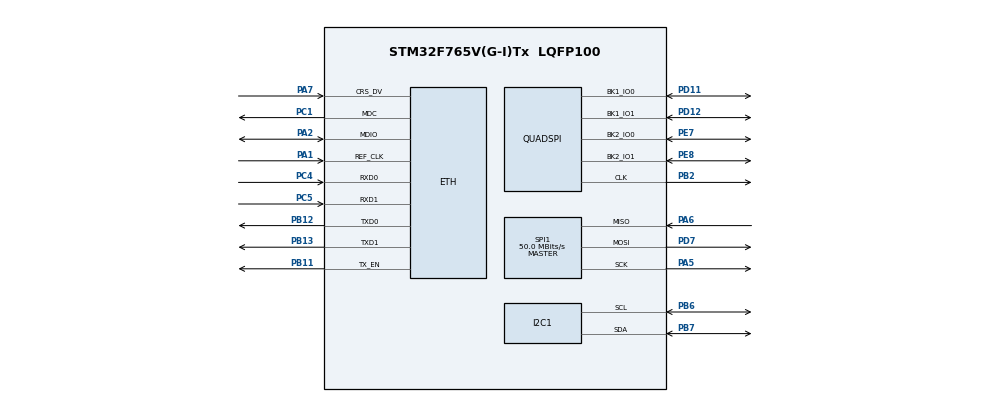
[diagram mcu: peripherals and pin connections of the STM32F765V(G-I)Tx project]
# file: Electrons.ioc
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CORTEX_M7.ART_ACCELERATOR_ENABLE=1
CORTEX_M7.CPU_DCache=Enabled
CORTEX_M7.CPU_ICache=Enabled
CORTEX_M7.PREFETCH_ENABLE=1
ETH.MediaInterface=HAL_ETH_RMII_MODE
I2C1.Timing=0x00C0EAFF
Mcu.Family=STM32F7
Mcu.Name=STM32F765V(G-I)Tx
Mcu.Package=LQFP100
NVIC.PriorityGroup=NVIC_PRIORITYGROUP_4
PA1.Mode=RMII
PA1.Signal=ETH_REF_CLK
PA2.Mode=RMII
PA2.Signal=ETH_MDIO
PA5.Mode=Full_Duplex_Master
PA5.Signal=SPI1_SCK
PA6.Mode=Full_Duplex_Master
PA6.Signal=SPI1_MISO
PA7.Mode=RMII
PA7.Signal=ETH_CRS_DV
PB11.Mode=RMII
PB11.Signal=ETH_TX_EN
PB12.Mode=RMII
PB12.Signal=ETH_TXD0
PB13.Mode=RMII
PB13.Signal=ETH_TXD1
PB2.Mode=Dual_Bank_2IOs
PB2.Signal=QUADSPI_CLK
PB6.Mode=I2C
PB6.Signal=I2C1_SCL
PB7.Mode=I2C
PB7.Signal=I2C1_SDA
PC1.Mode=RMII
PC1.Signal=ETH_MDC
PC4.Mode=RMII
PC4.Signal=ETH_RXD0
PC5.Mode=RMII
PC5.Signal=ETH_RXD1
PD11.Mode=Dual_Bank_2IOs
PD11.Signal=QUADSPI_BK1_IO0
PD12.Mode=Dual_Bank_2IOs
PD12.Signal=QUADSPI_BK1_IO1
PD7.Mode=Full_Duplex_Master
PD7.Signal=SPI1_MOSI
PE7.Mode=Dual_Bank_2IOs
PE7.Signal=QUADSPI_BK2_IO0
PE8.Mode=Dual_Bank_2IOs
PE8.Signal=QUADSPI_BK2_IO1
ProjectManager.HeapSize=0x200
ProjectManager.StackSize=0x400
ProjectManager.TargetToolchain=EWARM V8.50
RCC.AHBFreq_Value=100000000
RCC.APB1CLKDivider=RCC_HCLK_DIV2
RCC.APB1Freq_Value=50000000
RCC.APB1TimFreq_Value=100000000
RCC.APB2Freq_Value=100000000
RCC.APB2TimFreq_Value=100000000
RCC.CortexFreq_Value=100000000
RCC.HCLKFreq_Value=100000000
RCC.HSE_VALUE=25000000
RCC.HSI_VALUE=16000000
RCC.LSE_VALUE=32768
RCC.PLLM=8
RCC.PLLN=100
RCC.SYSCLKFreq_VALUE=100000000
RCC.SYSCLKSource=RCC_SYSCLKSOURCE_PLLCLK
RCC.USBFreq_Value=100000000
RCC.VCOOutputFreq_Value=200000000
SPI1.CalculateBaudRate=50.0 MBits/s
SPI1.Direction=SPI_DIRECTION_2LINES
SPI1.Mode=SPI_MODE_MASTER
SPI1.VirtualType=VM_MASTER
board=custom

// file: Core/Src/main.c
/* USER CODE BEGIN Header */
/**
  ******************************************************************************
  * @file           : main.c
  * @brief          : Main program body
  ******************************************************************************
  * @attention
  *
  * Copyright (c) 2024 STMicroelectronics.
  * All rights reserved.
  *
  * This software is licensed under terms that can be found in the LICENSE file
  * in the root directory of this software component.
  * If no LICENSE file comes with this software, it is provided AS-IS.
  *
  ******************************************************************************
  */
/* USER CODE END Header */
#include "main.h"
#include "string.h"

#if defined ( __ICCARM__ ) /*!< IAR Compiler */
#pragma location=0x2007c000
ETH_DMADescTypeDef  DMARxDscrTab[ETH_RX_DESC_CNT]; /* Ethernet Rx DMA Descriptors */
#pragma location=0x2007c0a0
ETH_DMADescTypeDef  DMATxDscrTab[ETH_TX_DESC_CNT]; /* Ethernet Tx DMA Descriptors */

#elif defined ( __CC_ARM )  /* MDK ARM Compiler */

__attribute__((at(0x2007c000))) ETH_DMADescTypeDef  DMARxDscrTab[ETH_RX_DESC_CNT]; /* Ethernet Rx DMA Descriptors */
__attribute__((at(0x2007c0a0))) ETH_DMADescTypeDef  DMATxDscrTab[ETH_TX_DESC_CNT]; /* Ethernet Tx DMA Descriptors */

#elif defined ( __GNUC__ ) /* GNU Compiler */
ETH_DMADescTypeDef DMARxDscrTab[ETH_RX_DESC_CNT] __attribute__((section(".RxDecripSection"))); /* Ethernet Rx DMA Descriptors */
ETH_DMADescTypeDef DMATxDscrTab[ETH_TX_DESC_CNT] __attribute__((section(".TxDecripSection")));   /* Ethernet Tx DMA Descriptors */

#endif

ETH_TxPacketConfig TxConfig;

ETH_HandleTypeDef heth;

I2C_HandleTypeDef hi2c1;

QSPI_HandleTypeDef hqspi;

SPI_HandleTypeDef hspi1;

void SystemClock_Config(void);
static void MPU_Config(void);
static void MX_GPIO_Init(void);
static void MX_ETH_Init(void);
static void MX_I2C1_Init(void);
static void MX_QUADSPI_Init(void);
static void MX_SPI1_Init(void);

int main(void)
{

  /* MPU Configuration--------------------------------------------------------*/
  MPU_Config();
/* Enable the CPU Cache */

  /* Enable I-Cache---------------------------------------------------------*/
  SCB_EnableICache();

  /* Enable D-Cache---------------------------------------------------------*/
  SCB_EnableDCache();

  /* MCU Configuration--------------------------------------------------------*/

  /* Reset of all peripherals, Initializes the Flash interface and the Systick. */
  HAL_Init();

  /* Configure the system clock */
  SystemClock_Config();

  /* Initialize all configured peripherals */
  MX_GPIO_Init();
  MX_ETH_Init();
  MX_I2C1_Init();
  MX_QUADSPI_Init();
  MX_SPI1_Init();

  /* Infinite loop */
  while (1)
  {

  }
}

void SystemClock_Config(void)
{
  RCC_OscInitTypeDef RCC_OscInitStruct = {0};
  RCC_ClkInitTypeDef RCC_ClkInitStruct = {0};

  /** Configure the main internal regulator output voltage
  */
  __HAL_RCC_PWR_CLK_ENABLE();
  __HAL_PWR_VOLTAGESCALING_CONFIG(PWR_REGULATOR_VOLTAGE_SCALE1);

  /** Initializes the RCC Oscillators according to the specified parameters
  * in the RCC_OscInitTypeDef structure.
  */
  RCC_OscInitStruct.OscillatorType = RCC_OSCILLATORTYPE_HSI;
  RCC_OscInitStruct.HSIState = RCC_HSI_ON;
  RCC_OscInitStruct.HSICalibrationValue = RCC_HSICALIBRATION_DEFAULT;
  RCC_OscInitStruct.PLL.PLLState = RCC_PLL_ON;
  RCC_OscInitStruct.PLL.PLLSource = RCC_PLLSOURCE_HSI;
  RCC_OscInitStruct.PLL.PLLM = 8;
  RCC_OscInitStruct.PLL.PLLN = 216;
  RCC_OscInitStruct.PLL.PLLP = RCC_PLLP_DIV2;
  RCC_OscInitStruct.PLL.PLLQ = 2;
  RCC_OscInitStruct.PLL.PLLR = 2;
  if (HAL_RCC_OscConfig(&RCC_OscInitStruct) != HAL_OK)
  {
    Error_Handler();
  }

  /** Activate the Over-Drive mode
  */
  if (HAL_PWREx_EnableOverDrive() != HAL_OK)
  {
    Error_Handler();
  }

  /** Initializes the CPU, AHB and APB buses clocks
  */
  RCC_ClkInitStruct.ClockType = RCC_CLOCKTYPE_HCLK|RCC_CLOCKTYPE_SYSCLK
                              |RCC_CLOCKTYPE_PCLK1|RCC_CLOCKTYPE_PCLK2;
  RCC_ClkInitStruct.SYSCLKSource = RCC_SYSCLKSOURCE_PLLCLK;
  RCC_ClkInitStruct.AHBCLKDivider = RCC_SYSCLK_DIV1;
  RCC_ClkInitStruct.APB1CLKDivider = RCC_HCLK_DIV4;
  RCC_ClkInitStruct.APB2CLKDivider = RCC_HCLK_DIV2;

  if (HAL_RCC_ClockConfig(&RCC_ClkInitStruct, FLASH_LATENCY_7) != HAL_OK)
  {
    Error_Handler();
  }
}

static void MX_ETH_Init(void)
{

   static uint8_t MACAddr[6];

  heth.Instance = ETH;
  MACAddr[0] = 0x00;
  MACAddr[1] = 0x80;
  MACAddr[2] = 0xE1;
  MACAddr[3] = 0x00;
  MACAddr[4] = 0x00;
  MACAddr[5] = 0x00;
  heth.Init.MACAddr = &MACAddr[0];
  heth.Init.MediaInterface = HAL_ETH_RMII_MODE;
  heth.Init.TxDesc = DMATxDscrTab;
  heth.Init.RxDesc = DMARxDscrTab;
  heth.Init.RxBuffLen = 1524;

  if (HAL_ETH_Init(&heth) != HAL_OK)
  {
    Error_Handler();
  }

  memset(&TxConfig, 0 , sizeof(ETH_TxPacketConfig));
  TxConfig.Attributes = ETH_TX_PACKETS_FEATURES_CSUM | ETH_TX_PACKETS_FEATURES_CRCPAD;
  TxConfig.ChecksumCtrl = ETH_CHECKSUM_IPHDR_PAYLOAD_INSERT_PHDR_CALC;
  TxConfig.CRCPadCtrl = ETH_CRC_PAD_INSERT;

}

static void MX_I2C1_Init(void)
{

  hi2c1.Instance = I2C1;
  hi2c1.Init.Timing = 0x20404768;
  hi2c1.Init.OwnAddress1 = 0;
  hi2c1.Init.AddressingMode = I2C_ADDRESSINGMODE_7BIT;
  hi2c1.Init.DualAddressMode = I2C_DUALADDRESS_DISABLE;
  hi2c1.Init.OwnAddress2 = 0;
  hi2c1.Init.OwnAddress2Masks = I2C_OA2_NOMASK;
  hi2c1.Init.GeneralCallMode = I2C_GENERALCALL_DISABLE;
  hi2c1.Init.NoStretchMode = I2C_NOSTRETCH_DISABLE;
  if (HAL_I2C_Init(&hi2c1) != HAL_OK)
  {
    Error_Handler();
  }

  /** Configure Analogue filter
  */
  if (HAL_I2CEx_ConfigAnalogFilter(&hi2c1, I2C_ANALOGFILTER_ENABLE) != HAL_OK)
  {
    Error_Handler();
  }

  /** Configure Digital filter
  */
  if (HAL_I2CEx_ConfigDigitalFilter(&hi2c1, 0) != HAL_OK)
  {
    Error_Handler();
  }

}

static void MX_QUADSPI_Init(void)
{

  /* QUADSPI parameter configuration*/
  hqspi.Instance = QUADSPI;
  hqspi.Init.ClockPrescaler = 255;
  hqspi.Init.FifoThreshold = 1;
  hqspi.Init.SampleShifting = QSPI_SAMPLE_SHIFTING_NONE;
  hqspi.Init.FlashSize = 1;
  hqspi.Init.ChipSelectHighTime = QSPI_CS_HIGH_TIME_1_CYCLE;
  hqspi.Init.ClockMode = QSPI_CLOCK_MODE_0;
  hqspi.Init.FlashID = QSPI_FLASH_ID_1;
  hqspi.Init.DualFlash = QSPI_DUALFLASH_DISABLE;
  if (HAL_QSPI_Init(&hqspi) != HAL_OK)
  {
    Error_Handler();
  }

}

static void MX_SPI1_Init(void)
{

  /* SPI1 parameter configuration*/
  hspi1.Instance = SPI1;
  hspi1.Init.Mode = SPI_MODE_MASTER;
  hspi1.Init.Direction = SPI_DIRECTION_2LINES;
  hspi1.Init.DataSize = SPI_DATASIZE_4BIT;
  hspi1.Init.CLKPolarity = SPI_POLARITY_LOW;
  hspi1.Init.CLKPhase = SPI_PHASE_1EDGE;
  hspi1.Init.NSS = SPI_NSS_SOFT;
  hspi1.Init.BaudRatePrescaler = SPI_BAUDRATEPRESCALER_2;
  hspi1.Init.FirstBit = SPI_FIRSTBIT_MSB;
  hspi1.Init.TIMode = SPI_TIMODE_DISABLE;
  hspi1.Init.CRCCalculation = SPI_CRCCALCULATION_DISABLE;
  hspi1.Init.CRCPolynomial = 7;
  hspi1.Init.CRCLength = SPI_CRC_LENGTH_DATASIZE;
  hspi1.Init.NSSPMode = SPI_NSS_PULSE_ENABLE;
  if (HAL_SPI_Init(&hspi1) != HAL_OK)
  {
    Error_Handler();
  }

}

static void MX_GPIO_Init(void)
{

  /* GPIO Ports Clock Enable */
  __HAL_RCC_GPIOE_CLK_ENABLE();
  __HAL_RCC_GPIOC_CLK_ENABLE();
  __HAL_RCC_GPIOA_CLK_ENABLE();
  __HAL_RCC_GPIOB_CLK_ENABLE();
  __HAL_RCC_GPIOD_CLK_ENABLE();

}

/* MPU Configuration */

void MPU_Config(void)
{
  MPU_Region_InitTypeDef MPU_InitStruct = {0};

  /* Disables the MPU */
  HAL_MPU_Disable();

  /** Initializes and configures the Region and the memory to be protected
  */
  MPU_InitStruct.Enable = MPU_REGION_ENABLE;
  MPU_InitStruct.Number = MPU_REGION_NUMBER0;
  MPU_InitStruct.BaseAddress = 0x0;
  MPU_InitStruct.Size = MPU_REGION_SIZE_4GB;
  MPU_InitStruct.SubRegionDisable = 0x87;
  MPU_InitStruct.TypeExtField = MPU_TEX_LEVEL0;
  MPU_InitStruct.AccessPermission = MPU_REGION_NO_ACCESS;
  MPU_InitStruct.DisableExec = MPU_INSTRUCTION_ACCESS_DISABLE;
  MPU_InitStruct.IsShareable = MPU_ACCESS_SHAREABLE;
  MPU_InitStruct.IsCacheable = MPU_ACCESS_NOT_CACHEABLE;
  MPU_InitStruct.IsBufferable = MPU_ACCESS_NOT_BUFFERABLE;

  HAL_MPU_ConfigRegion(&MPU_InitStruct);
  /* Enables the MPU */
  HAL_MPU_Enable(MPU_PRIVILEGED_DEFAULT);

}

void Error_Handler(void)
{
  __disable_irq();
  while (1)
  {
  }
}
